VERSION 5.7 ;
  NOWIREEXTENSIONATPIN ON ;
  DIVIDERCHAR "/" ;
  BUSBITCHARS "[]" ;
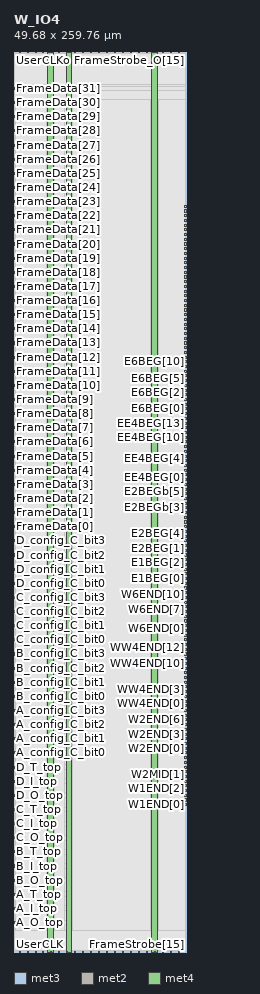
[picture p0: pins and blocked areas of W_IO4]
MACRO W_IO4
  CLASS BLOCK ;
  FOREIGN W_IO4 ;
  ORIGIN 0.000 0.000 ;
  SIZE 49.680 BY 259.760 ;
  PIN A_I_top
    DIRECTION OUTPUT ;
    USE SIGNAL ;
    ANTENNADIFFAREA 0.445500 ;
    PORT
      LAYER met3 ;
        RECT 0.000 12.280 0.600 12.880 ;
    END
  END A_I_top
  PIN A_O_top
    DIRECTION INPUT ;
    USE SIGNAL ;
    ANTENNAGATEAREA 0.159000 ;
    PORT
      LAYER met3 ;
        RECT 0.000 8.200 0.600 8.800 ;
    END
  END A_O_top
  PIN A_T_top
    DIRECTION OUTPUT ;
    USE SIGNAL ;
    ANTENNADIFFAREA 0.445500 ;
    PORT
      LAYER met3 ;
        RECT 0.000 16.360 0.600 16.960 ;
    END
  END A_T_top
  PIN A_config_C_bit0
    DIRECTION OUTPUT ;
    USE SIGNAL ;
    ANTENNADIFFAREA 0.445500 ;
    PORT
      LAYER met3 ;
        RECT 0.000 57.160 0.600 57.760 ;
    END
  END A_config_C_bit0
  PIN A_config_C_bit1
    DIRECTION OUTPUT ;
    USE SIGNAL ;
    ANTENNADIFFAREA 0.445500 ;
    PORT
      LAYER met3 ;
        RECT 0.000 61.240 0.600 61.840 ;
    END
  END A_config_C_bit1
  PIN A_config_C_bit2
    DIRECTION OUTPUT ;
    USE SIGNAL ;
    ANTENNADIFFAREA 0.445500 ;
    PORT
      LAYER met3 ;
        RECT 0.000 65.320 0.600 65.920 ;
    END
  END A_config_C_bit2
  PIN A_config_C_bit3
    DIRECTION OUTPUT ;
    USE SIGNAL ;
    ANTENNADIFFAREA 0.445500 ;
    PORT
      LAYER met3 ;
        RECT 0.000 69.400 0.600 70.000 ;
    END
  END A_config_C_bit3
  PIN B_I_top
    DIRECTION OUTPUT ;
    USE SIGNAL ;
    ANTENNADIFFAREA 0.445500 ;
    PORT
      LAYER met3 ;
        RECT 0.000 24.520 0.600 25.120 ;
    END
  END B_I_top
  PIN B_O_top
    DIRECTION INPUT ;
    USE SIGNAL ;
    ANTENNAGATEAREA 0.159000 ;
    PORT
      LAYER met3 ;
        RECT 0.000 20.440 0.600 21.040 ;
    END
  END B_O_top
  PIN B_T_top
    DIRECTION OUTPUT ;
    USE SIGNAL ;
    ANTENNADIFFAREA 0.445500 ;
    PORT
      LAYER met3 ;
        RECT 0.000 28.600 0.600 29.200 ;
    END
  END B_T_top
  PIN B_config_C_bit0
    DIRECTION OUTPUT ;
    USE SIGNAL ;
    ANTENNADIFFAREA 0.445500 ;
    PORT
      LAYER met3 ;
        RECT 0.000 73.480 0.600 74.080 ;
    END
  END B_config_C_bit0
  PIN B_config_C_bit1
    DIRECTION OUTPUT ;
    USE SIGNAL ;
    ANTENNADIFFAREA 0.445500 ;
    PORT
      LAYER met3 ;
        RECT 0.000 77.560 0.600 78.160 ;
    END
  END B_config_C_bit1
  PIN B_config_C_bit2
    DIRECTION OUTPUT ;
    USE SIGNAL ;
    ANTENNADIFFAREA 0.445500 ;
    PORT
      LAYER met3 ;
        RECT 0.000 81.640 0.600 82.240 ;
    END
  END B_config_C_bit2
  PIN B_config_C_bit3
    DIRECTION OUTPUT ;
    USE SIGNAL ;
    ANTENNADIFFAREA 0.445500 ;
    PORT
      LAYER met3 ;
        RECT 0.000 85.720 0.600 86.320 ;
    END
  END B_config_C_bit3
  PIN C_I_top
    DIRECTION OUTPUT ;
    USE SIGNAL ;
    ANTENNADIFFAREA 0.445500 ;
    PORT
      LAYER met3 ;
        RECT 0.000 36.760 0.600 37.360 ;
    END
  END C_I_top
  PIN C_O_top
    DIRECTION INPUT ;
    USE SIGNAL ;
    ANTENNAGATEAREA 0.159000 ;
    PORT
      LAYER met3 ;
        RECT 0.000 32.680 0.600 33.280 ;
    END
  END C_O_top
  PIN C_T_top
    DIRECTION OUTPUT ;
    USE SIGNAL ;
    ANTENNADIFFAREA 0.445500 ;
    PORT
      LAYER met3 ;
        RECT 0.000 40.840 0.600 41.440 ;
    END
  END C_T_top
  PIN C_config_C_bit0
    DIRECTION OUTPUT ;
    USE SIGNAL ;
    ANTENNADIFFAREA 0.445500 ;
    PORT
      LAYER met3 ;
        RECT 0.000 89.800 0.600 90.400 ;
    END
  END C_config_C_bit0
  PIN C_config_C_bit1
    DIRECTION OUTPUT ;
    USE SIGNAL ;
    ANTENNADIFFAREA 0.445500 ;
    PORT
      LAYER met3 ;
        RECT 0.000 93.880 0.600 94.480 ;
    END
  END C_config_C_bit1
  PIN C_config_C_bit2
    DIRECTION OUTPUT ;
    USE SIGNAL ;
    ANTENNADIFFAREA 0.445500 ;
    PORT
      LAYER met3 ;
        RECT 0.000 97.960 0.600 98.560 ;
    END
  END C_config_C_bit2
  PIN C_config_C_bit3
    DIRECTION OUTPUT ;
    USE SIGNAL ;
    ANTENNADIFFAREA 0.445500 ;
    PORT
      LAYER met3 ;
        RECT 0.000 102.040 0.600 102.640 ;
    END
  END C_config_C_bit3
  PIN D_I_top
    DIRECTION OUTPUT ;
    USE SIGNAL ;
    ANTENNADIFFAREA 0.445500 ;
    PORT
      LAYER met3 ;
        RECT 0.000 49.000 0.600 49.600 ;
    END
  END D_I_top
  PIN D_O_top
    DIRECTION INPUT ;
    USE SIGNAL ;
    ANTENNAGATEAREA 0.213000 ;
    PORT
      LAYER met3 ;
        RECT 0.000 44.920 0.600 45.520 ;
    END
  END D_O_top
  PIN D_T_top
    DIRECTION OUTPUT ;
    USE SIGNAL ;
    ANTENNADIFFAREA 0.445500 ;
    PORT
      LAYER met3 ;
        RECT 0.000 53.080 0.600 53.680 ;
    END
  END D_T_top
  PIN D_config_C_bit0
    DIRECTION OUTPUT ;
    USE SIGNAL ;
    ANTENNADIFFAREA 0.445500 ;
    PORT
      LAYER met3 ;
        RECT 0.000 106.120 0.600 106.720 ;
    END
  END D_config_C_bit0
  PIN D_config_C_bit1
    DIRECTION OUTPUT ;
    USE SIGNAL ;
    ANTENNADIFFAREA 0.445500 ;
    PORT
      LAYER met3 ;
        RECT 0.000 110.200 0.600 110.800 ;
    END
  END D_config_C_bit1
  PIN D_config_C_bit2
    DIRECTION OUTPUT ;
    USE SIGNAL ;
    ANTENNADIFFAREA 0.445500 ;
    PORT
      LAYER met3 ;
        RECT 0.000 114.280 0.600 114.880 ;
    END
  END D_config_C_bit2
  PIN D_config_C_bit3
    DIRECTION OUTPUT ;
    USE SIGNAL ;
    ANTENNADIFFAREA 0.445500 ;
    PORT
      LAYER met3 ;
        RECT 0.000 118.360 0.600 118.960 ;
    END
  END D_config_C_bit3
  PIN E1BEG[0]
    DIRECTION OUTPUT ;
    USE SIGNAL ;
    ANTENNADIFFAREA 0.445500 ;
    PORT
      LAYER met3 ;
        RECT 49.080 107.480 49.680 108.080 ;
    END
  END E1BEG[0]
  PIN E1BEG[1]
    DIRECTION OUTPUT ;
    USE SIGNAL ;
    ANTENNADIFFAREA 0.445500 ;
    PORT
      LAYER met3 ;
        RECT 49.080 108.840 49.680 109.440 ;
    END
  END E1BEG[1]
  PIN E1BEG[2]
    DIRECTION OUTPUT ;
    USE SIGNAL ;
    ANTENNADIFFAREA 0.445500 ;
    PORT
      LAYER met3 ;
        RECT 49.080 110.200 49.680 110.800 ;
    END
  END E1BEG[2]
  PIN E1BEG[3]
    DIRECTION OUTPUT ;
    USE SIGNAL ;
    ANTENNADIFFAREA 0.445500 ;
    PORT
      LAYER met3 ;
        RECT 49.080 111.560 49.680 112.160 ;
    END
  END E1BEG[3]
  PIN E2BEG[0]
    DIRECTION OUTPUT ;
    USE SIGNAL ;
    ANTENNADIFFAREA 0.445500 ;
    PORT
      LAYER met3 ;
        RECT 49.080 112.920 49.680 113.520 ;
    END
  END E2BEG[0]
  PIN E2BEG[1]
    DIRECTION OUTPUT ;
    USE SIGNAL ;
    ANTENNADIFFAREA 0.445500 ;
    PORT
      LAYER met3 ;
        RECT 49.080 114.280 49.680 114.880 ;
    END
  END E2BEG[1]
  PIN E2BEG[2]
    DIRECTION OUTPUT ;
    USE SIGNAL ;
    ANTENNADIFFAREA 0.445500 ;
    PORT
      LAYER met3 ;
        RECT 49.080 115.640 49.680 116.240 ;
    END
  END E2BEG[2]
  PIN E2BEG[3]
    DIRECTION OUTPUT ;
    USE SIGNAL ;
    ANTENNADIFFAREA 0.445500 ;
    PORT
      LAYER met3 ;
        RECT 49.080 117.000 49.680 117.600 ;
    END
  END E2BEG[3]
  PIN E2BEG[4]
    DIRECTION OUTPUT ;
    USE SIGNAL ;
    ANTENNADIFFAREA 0.445500 ;
    PORT
      LAYER met3 ;
        RECT 49.080 118.360 49.680 118.960 ;
    END
  END E2BEG[4]
  PIN E2BEG[5]
    DIRECTION OUTPUT ;
    USE SIGNAL ;
    ANTENNADIFFAREA 0.445500 ;
    PORT
      LAYER met3 ;
        RECT 49.080 119.720 49.680 120.320 ;
    END
  END E2BEG[5]
  PIN E2BEG[6]
    DIRECTION OUTPUT ;
    USE SIGNAL ;
    ANTENNADIFFAREA 0.445500 ;
    PORT
      LAYER met3 ;
        RECT 49.080 121.080 49.680 121.680 ;
    END
  END E2BEG[6]
  PIN E2BEG[7]
    DIRECTION OUTPUT ;
    USE SIGNAL ;
    ANTENNADIFFAREA 0.445500 ;
    PORT
      LAYER met3 ;
        RECT 49.080 122.440 49.680 123.040 ;
    END
  END E2BEG[7]
  PIN E2BEGb[0]
    DIRECTION OUTPUT ;
    USE SIGNAL ;
    ANTENNADIFFAREA 0.445500 ;
    PORT
      LAYER met3 ;
        RECT 49.080 123.800 49.680 124.400 ;
    END
  END E2BEGb[0]
  PIN E2BEGb[1]
    DIRECTION OUTPUT ;
    USE SIGNAL ;
    ANTENNADIFFAREA 0.445500 ;
    PORT
      LAYER met3 ;
        RECT 49.080 125.160 49.680 125.760 ;
    END
  END E2BEGb[1]
  PIN E2BEGb[2]
    DIRECTION OUTPUT ;
    USE SIGNAL ;
    ANTENNADIFFAREA 0.445500 ;
    PORT
      LAYER met3 ;
        RECT 49.080 126.520 49.680 127.120 ;
    END
  END E2BEGb[2]
  PIN E2BEGb[3]
    DIRECTION OUTPUT ;
    USE SIGNAL ;
    ANTENNADIFFAREA 0.445500 ;
    PORT
      LAYER met3 ;
        RECT 49.080 127.880 49.680 128.480 ;
    END
  END E2BEGb[3]
  PIN E2BEGb[4]
    DIRECTION OUTPUT ;
    USE SIGNAL ;
    ANTENNADIFFAREA 0.445500 ;
    PORT
      LAYER met3 ;
        RECT 49.080 129.240 49.680 129.840 ;
    END
  END E2BEGb[4]
  PIN E2BEGb[5]
    DIRECTION OUTPUT ;
    USE SIGNAL ;
    ANTENNADIFFAREA 0.445500 ;
    PORT
      LAYER met3 ;
        RECT 49.080 130.600 49.680 131.200 ;
    END
  END E2BEGb[5]
  PIN E2BEGb[6]
    DIRECTION OUTPUT ;
    USE SIGNAL ;
    ANTENNADIFFAREA 0.445500 ;
    PORT
      LAYER met3 ;
        RECT 49.080 131.960 49.680 132.560 ;
    END
  END E2BEGb[6]
  PIN E2BEGb[7]
    DIRECTION OUTPUT ;
    USE SIGNAL ;
    ANTENNADIFFAREA 0.445500 ;
    PORT
      LAYER met3 ;
        RECT 49.080 133.320 49.680 133.920 ;
    END
  END E2BEGb[7]
  PIN E6BEG[0]
    DIRECTION OUTPUT ;
    USE SIGNAL ;
    ANTENNADIFFAREA 0.445500 ;
    PORT
      LAYER met3 ;
        RECT 49.080 156.440 49.680 157.040 ;
    END
  END E6BEG[0]
  PIN E6BEG[10]
    DIRECTION OUTPUT ;
    USE SIGNAL ;
    ANTENNADIFFAREA 0.445500 ;
    PORT
      LAYER met3 ;
        RECT 49.080 170.040 49.680 170.640 ;
    END
  END E6BEG[10]
  PIN E6BEG[11]
    DIRECTION OUTPUT ;
    USE SIGNAL ;
    ANTENNADIFFAREA 0.445500 ;
    PORT
      LAYER met3 ;
        RECT 49.080 171.400 49.680 172.000 ;
    END
  END E6BEG[11]
  PIN E6BEG[1]
    DIRECTION OUTPUT ;
    USE SIGNAL ;
    ANTENNADIFFAREA 0.445500 ;
    PORT
      LAYER met3 ;
        RECT 49.080 157.800 49.680 158.400 ;
    END
  END E6BEG[1]
  PIN E6BEG[2]
    DIRECTION OUTPUT ;
    USE SIGNAL ;
    ANTENNADIFFAREA 0.445500 ;
    PORT
      LAYER met3 ;
        RECT 49.080 159.160 49.680 159.760 ;
    END
  END E6BEG[2]
  PIN E6BEG[3]
    DIRECTION OUTPUT ;
    USE SIGNAL ;
    ANTENNADIFFAREA 0.445500 ;
    PORT
      LAYER met3 ;
        RECT 49.080 160.520 49.680 161.120 ;
    END
  END E6BEG[3]
  PIN E6BEG[4]
    DIRECTION OUTPUT ;
    USE SIGNAL ;
    ANTENNADIFFAREA 0.445500 ;
    PORT
      LAYER met3 ;
        RECT 49.080 161.880 49.680 162.480 ;
    END
  END E6BEG[4]
  PIN E6BEG[5]
    DIRECTION OUTPUT ;
    USE SIGNAL ;
    ANTENNADIFFAREA 0.445500 ;
    PORT
      LAYER met3 ;
        RECT 49.080 163.240 49.680 163.840 ;
    END
  END E6BEG[5]
  PIN E6BEG[6]
    DIRECTION OUTPUT ;
    USE SIGNAL ;
    ANTENNADIFFAREA 0.445500 ;
    PORT
      LAYER met3 ;
        RECT 49.080 164.600 49.680 165.200 ;
    END
  END E6BEG[6]
  PIN E6BEG[7]
    DIRECTION OUTPUT ;
    USE SIGNAL ;
    ANTENNADIFFAREA 0.445500 ;
    PORT
      LAYER met3 ;
        RECT 49.080 165.960 49.680 166.560 ;
    END
  END E6BEG[7]
  PIN E6BEG[8]
    DIRECTION OUTPUT ;
    USE SIGNAL ;
    ANTENNADIFFAREA 0.445500 ;
    PORT
      LAYER met3 ;
        RECT 49.080 167.320 49.680 167.920 ;
    END
  END E6BEG[8]
  PIN E6BEG[9]
    DIRECTION OUTPUT ;
    USE SIGNAL ;
    ANTENNADIFFAREA 0.445500 ;
    PORT
      LAYER met3 ;
        RECT 49.080 168.680 49.680 169.280 ;
    END
  END E6BEG[9]
  PIN EE4BEG[0]
    DIRECTION OUTPUT ;
    USE SIGNAL ;
    ANTENNADIFFAREA 0.445500 ;
    PORT
      LAYER met3 ;
        RECT 49.080 134.680 49.680 135.280 ;
    END
  END EE4BEG[0]
  PIN EE4BEG[10]
    DIRECTION OUTPUT ;
    USE SIGNAL ;
    ANTENNADIFFAREA 0.445500 ;
    PORT
      LAYER met3 ;
        RECT 49.080 148.280 49.680 148.880 ;
    END
  END EE4BEG[10]
  PIN EE4BEG[11]
    DIRECTION OUTPUT ;
    USE SIGNAL ;
    ANTENNADIFFAREA 0.445500 ;
    PORT
      LAYER met3 ;
        RECT 49.080 149.640 49.680 150.240 ;
    END
  END EE4BEG[11]
  PIN EE4BEG[12]
    DIRECTION OUTPUT ;
    USE SIGNAL ;
    ANTENNADIFFAREA 0.445500 ;
    PORT
      LAYER met3 ;
        RECT 49.080 151.000 49.680 151.600 ;
    END
  END EE4BEG[12]
  PIN EE4BEG[13]
    DIRECTION OUTPUT ;
    USE SIGNAL ;
    ANTENNADIFFAREA 0.445500 ;
    PORT
      LAYER met3 ;
        RECT 49.080 152.360 49.680 152.960 ;
    END
  END EE4BEG[13]
  PIN EE4BEG[14]
    DIRECTION OUTPUT ;
    USE SIGNAL ;
    ANTENNADIFFAREA 0.445500 ;
    PORT
      LAYER met3 ;
        RECT 49.080 153.720 49.680 154.320 ;
    END
  END EE4BEG[14]
  PIN EE4BEG[15]
    DIRECTION OUTPUT ;
    USE SIGNAL ;
    ANTENNADIFFAREA 0.445500 ;
    PORT
      LAYER met3 ;
        RECT 49.080 155.080 49.680 155.680 ;
    END
  END EE4BEG[15]
  PIN EE4BEG[1]
    DIRECTION OUTPUT ;
    USE SIGNAL ;
    ANTENNADIFFAREA 0.445500 ;
    PORT
      LAYER met3 ;
        RECT 49.080 136.040 49.680 136.640 ;
    END
  END EE4BEG[1]
  PIN EE4BEG[2]
    DIRECTION OUTPUT ;
    USE SIGNAL ;
    ANTENNADIFFAREA 0.445500 ;
    PORT
      LAYER met3 ;
        RECT 49.080 137.400 49.680 138.000 ;
    END
  END EE4BEG[2]
  PIN EE4BEG[3]
    DIRECTION OUTPUT ;
    USE SIGNAL ;
    ANTENNADIFFAREA 0.445500 ;
    PORT
      LAYER met3 ;
        RECT 49.080 138.760 49.680 139.360 ;
    END
  END EE4BEG[3]
  PIN EE4BEG[4]
    DIRECTION OUTPUT ;
    USE SIGNAL ;
    ANTENNADIFFAREA 0.445500 ;
    PORT
      LAYER met3 ;
        RECT 49.080 140.120 49.680 140.720 ;
    END
  END EE4BEG[4]
  PIN EE4BEG[5]
    DIRECTION OUTPUT ;
    USE SIGNAL ;
    ANTENNADIFFAREA 0.445500 ;
    PORT
      LAYER met3 ;
        RECT 49.080 141.480 49.680 142.080 ;
    END
  END EE4BEG[5]
  PIN EE4BEG[6]
    DIRECTION OUTPUT ;
    USE SIGNAL ;
    ANTENNADIFFAREA 0.445500 ;
    PORT
      LAYER met3 ;
        RECT 49.080 142.840 49.680 143.440 ;
    END
  END EE4BEG[6]
  PIN EE4BEG[7]
    DIRECTION OUTPUT ;
    USE SIGNAL ;
    ANTENNADIFFAREA 0.445500 ;
    PORT
      LAYER met3 ;
        RECT 49.080 144.200 49.680 144.800 ;
    END
  END EE4BEG[7]
  PIN EE4BEG[8]
    DIRECTION OUTPUT ;
    USE SIGNAL ;
    ANTENNADIFFAREA 0.445500 ;
    PORT
      LAYER met3 ;
        RECT 49.080 145.560 49.680 146.160 ;
    END
  END EE4BEG[8]
  PIN EE4BEG[9]
    DIRECTION OUTPUT ;
    USE SIGNAL ;
    ANTENNADIFFAREA 0.445500 ;
    PORT
      LAYER met3 ;
        RECT 49.080 146.920 49.680 147.520 ;
    END
  END EE4BEG[9]
  PIN FrameData[0]
    DIRECTION INPUT ;
    USE SIGNAL ;
    ANTENNAGATEAREA 0.196500 ;
    PORT
      LAYER met3 ;
        RECT 0.000 122.440 0.600 123.040 ;
    END
  END FrameData[0]
  PIN FrameData[10]
    DIRECTION INPUT ;
    USE SIGNAL ;
    ANTENNAGATEAREA 0.213000 ;
    PORT
      LAYER met3 ;
        RECT 0.000 163.240 0.600 163.840 ;
    END
  END FrameData[10]
  PIN FrameData[11]
    DIRECTION INPUT ;
    USE SIGNAL ;
    ANTENNAGATEAREA 0.213000 ;
    PORT
      LAYER met3 ;
        RECT 0.000 167.320 0.600 167.920 ;
    END
  END FrameData[11]
  PIN FrameData[12]
    DIRECTION INPUT ;
    USE SIGNAL ;
    ANTENNAGATEAREA 0.213000 ;
    PORT
      LAYER met3 ;
        RECT 0.000 171.400 0.600 172.000 ;
    END
  END FrameData[12]
  PIN FrameData[13]
    DIRECTION INPUT ;
    USE SIGNAL ;
    ANTENNAGATEAREA 0.213000 ;
    PORT
      LAYER met3 ;
        RECT 0.000 175.480 0.600 176.080 ;
    END
  END FrameData[13]
  PIN FrameData[14]
    DIRECTION INPUT ;
    USE SIGNAL ;
    ANTENNAGATEAREA 0.213000 ;
    PORT
      LAYER met3 ;
        RECT 0.000 179.560 0.600 180.160 ;
    END
  END FrameData[14]
  PIN FrameData[15]
    DIRECTION INPUT ;
    USE SIGNAL ;
    ANTENNAGATEAREA 0.213000 ;
    PORT
      LAYER met3 ;
        RECT 0.000 183.640 0.600 184.240 ;
    END
  END FrameData[15]
  PIN FrameData[16]
    DIRECTION INPUT ;
    USE SIGNAL ;
    ANTENNAGATEAREA 0.196500 ;
    PORT
      LAYER met3 ;
        RECT 0.000 187.720 0.600 188.320 ;
    END
  END FrameData[16]
  PIN FrameData[17]
    DIRECTION INPUT ;
    USE SIGNAL ;
    ANTENNAGATEAREA 0.196500 ;
    PORT
      LAYER met3 ;
        RECT 0.000 191.800 0.600 192.400 ;
    END
  END FrameData[17]
  PIN FrameData[18]
    DIRECTION INPUT ;
    USE SIGNAL ;
    ANTENNAGATEAREA 0.213000 ;
    PORT
      LAYER met3 ;
        RECT 0.000 195.880 0.600 196.480 ;
    END
  END FrameData[18]
  PIN FrameData[19]
    DIRECTION INPUT ;
    USE SIGNAL ;
    ANTENNAGATEAREA 0.213000 ;
    PORT
      LAYER met3 ;
        RECT 0.000 199.960 0.600 200.560 ;
    END
  END FrameData[19]
  PIN FrameData[1]
    DIRECTION INPUT ;
    USE SIGNAL ;
    ANTENNAGATEAREA 0.196500 ;
    PORT
      LAYER met3 ;
        RECT 0.000 126.520 0.600 127.120 ;
    END
  END FrameData[1]
  PIN FrameData[20]
    DIRECTION INPUT ;
    USE SIGNAL ;
    ANTENNAGATEAREA 0.159000 ;
    PORT
      LAYER met3 ;
        RECT 0.000 204.040 0.600 204.640 ;
    END
  END FrameData[20]
  PIN FrameData[21]
    DIRECTION INPUT ;
    USE SIGNAL ;
    ANTENNAGATEAREA 0.159000 ;
    PORT
      LAYER met3 ;
        RECT 0.000 208.120 0.600 208.720 ;
    END
  END FrameData[21]
  PIN FrameData[22]
    DIRECTION INPUT ;
    USE SIGNAL ;
    ANTENNAGATEAREA 0.159000 ;
    PORT
      LAYER met3 ;
        RECT 0.000 212.200 0.600 212.800 ;
    END
  END FrameData[22]
  PIN FrameData[23]
    DIRECTION INPUT ;
    USE SIGNAL ;
    ANTENNAGATEAREA 0.159000 ;
    PORT
      LAYER met3 ;
        RECT 0.000 216.280 0.600 216.880 ;
    END
  END FrameData[23]
  PIN FrameData[24]
    DIRECTION INPUT ;
    USE SIGNAL ;
    ANTENNAGATEAREA 0.159000 ;
    PORT
      LAYER met3 ;
        RECT 0.000 220.360 0.600 220.960 ;
    END
  END FrameData[24]
  PIN FrameData[25]
    DIRECTION INPUT ;
    USE SIGNAL ;
    ANTENNAGATEAREA 0.213000 ;
    PORT
      LAYER met3 ;
        RECT 0.000 224.440 0.600 225.040 ;
    END
  END FrameData[25]
  PIN FrameData[26]
    DIRECTION INPUT ;
    USE SIGNAL ;
    ANTENNAGATEAREA 0.159000 ;
    PORT
      LAYER met3 ;
        RECT 0.000 228.520 0.600 229.120 ;
    END
  END FrameData[26]
  PIN FrameData[27]
    DIRECTION INPUT ;
    USE SIGNAL ;
    ANTENNAGATEAREA 0.159000 ;
    PORT
      LAYER met3 ;
        RECT 0.000 232.600 0.600 233.200 ;
    END
  END FrameData[27]
  PIN FrameData[28]
    DIRECTION INPUT ;
    USE SIGNAL ;
    ANTENNAGATEAREA 0.159000 ;
    PORT
      LAYER met3 ;
        RECT 0.000 236.680 0.600 237.280 ;
    END
  END FrameData[28]
  PIN FrameData[29]
    DIRECTION INPUT ;
    USE SIGNAL ;
    ANTENNAGATEAREA 0.213000 ;
    PORT
      LAYER met3 ;
        RECT 0.000 240.760 0.600 241.360 ;
    END
  END FrameData[29]
  PIN FrameData[2]
    DIRECTION INPUT ;
    USE SIGNAL ;
    ANTENNAGATEAREA 0.126000 ;
    PORT
      LAYER met3 ;
        RECT 0.000 130.600 0.600 131.200 ;
    END
  END FrameData[2]
  PIN FrameData[30]
    DIRECTION INPUT ;
    USE SIGNAL ;
    ANTENNAGATEAREA 0.159000 ;
    PORT
      LAYER met3 ;
        RECT 0.000 244.840 0.600 245.440 ;
    END
  END FrameData[30]
  PIN FrameData[31]
    DIRECTION INPUT ;
    USE SIGNAL ;
    ANTENNAGATEAREA 0.159000 ;
    PORT
      LAYER met3 ;
        RECT 0.000 248.920 0.600 249.520 ;
    END
  END FrameData[31]
  PIN FrameData[3]
    DIRECTION INPUT ;
    USE SIGNAL ;
    ANTENNAGATEAREA 0.213000 ;
    PORT
      LAYER met3 ;
        RECT 0.000 134.680 0.600 135.280 ;
    END
  END FrameData[3]
  PIN FrameData[4]
    DIRECTION INPUT ;
    USE SIGNAL ;
    ANTENNAGATEAREA 0.213000 ;
    PORT
      LAYER met3 ;
        RECT 0.000 138.760 0.600 139.360 ;
    END
  END FrameData[4]
  PIN FrameData[5]
    DIRECTION INPUT ;
    USE SIGNAL ;
    ANTENNAGATEAREA 0.213000 ;
    PORT
      LAYER met3 ;
        RECT 0.000 142.840 0.600 143.440 ;
    END
  END FrameData[5]
  PIN FrameData[6]
    DIRECTION INPUT ;
    USE SIGNAL ;
    ANTENNAGATEAREA 0.213000 ;
    PORT
      LAYER met3 ;
        RECT 0.000 146.920 0.600 147.520 ;
    END
  END FrameData[6]
  PIN FrameData[7]
    DIRECTION INPUT ;
    USE SIGNAL ;
    ANTENNAGATEAREA 0.213000 ;
    PORT
      LAYER met3 ;
        RECT 0.000 151.000 0.600 151.600 ;
    END
  END FrameData[7]
  PIN FrameData[8]
    DIRECTION INPUT ;
    USE SIGNAL ;
    ANTENNAGATEAREA 0.213000 ;
    PORT
      LAYER met3 ;
        RECT 0.000 155.080 0.600 155.680 ;
    END
  END FrameData[8]
  PIN FrameData[9]
    DIRECTION INPUT ;
    USE SIGNAL ;
    ANTENNAGATEAREA 0.213000 ;
    PORT
      LAYER met3 ;
        RECT 0.000 159.160 0.600 159.760 ;
    END
  END FrameData[9]
  PIN FrameData_O[0]
    DIRECTION OUTPUT ;
    USE SIGNAL ;
    ANTENNADIFFAREA 0.445500 ;
    PORT
      LAYER met3 ;
        RECT 49.080 172.760 49.680 173.360 ;
    END
  END FrameData_O[0]
  PIN FrameData_O[10]
    DIRECTION OUTPUT ;
    USE SIGNAL ;
    ANTENNADIFFAREA 0.445500 ;
    PORT
      LAYER met3 ;
        RECT 49.080 186.360 49.680 186.960 ;
    END
  END FrameData_O[10]
  PIN FrameData_O[11]
    DIRECTION OUTPUT ;
    USE SIGNAL ;
    ANTENNADIFFAREA 0.445500 ;
    PORT
      LAYER met3 ;
        RECT 49.080 187.720 49.680 188.320 ;
    END
  END FrameData_O[11]
  PIN FrameData_O[12]
    DIRECTION OUTPUT ;
    USE SIGNAL ;
    ANTENNADIFFAREA 0.445500 ;
    PORT
      LAYER met3 ;
        RECT 49.080 189.080 49.680 189.680 ;
    END
  END FrameData_O[12]
  PIN FrameData_O[13]
    DIRECTION OUTPUT ;
    USE SIGNAL ;
    ANTENNADIFFAREA 0.445500 ;
    PORT
      LAYER met3 ;
        RECT 49.080 190.440 49.680 191.040 ;
    END
  END FrameData_O[13]
  PIN FrameData_O[14]
    DIRECTION OUTPUT ;
    USE SIGNAL ;
    ANTENNADIFFAREA 0.445500 ;
    PORT
      LAYER met3 ;
        RECT 49.080 191.800 49.680 192.400 ;
    END
  END FrameData_O[14]
  PIN FrameData_O[15]
    DIRECTION OUTPUT ;
    USE SIGNAL ;
    ANTENNADIFFAREA 0.445500 ;
    PORT
      LAYER met3 ;
        RECT 49.080 193.160 49.680 193.760 ;
    END
  END FrameData_O[15]
  PIN FrameData_O[16]
    DIRECTION OUTPUT ;
    USE SIGNAL ;
    ANTENNADIFFAREA 0.445500 ;
    PORT
      LAYER met3 ;
        RECT 49.080 194.520 49.680 195.120 ;
    END
  END FrameData_O[16]
  PIN FrameData_O[17]
    DIRECTION OUTPUT ;
    USE SIGNAL ;
    ANTENNADIFFAREA 0.445500 ;
    PORT
      LAYER met3 ;
        RECT 49.080 195.880 49.680 196.480 ;
    END
  END FrameData_O[17]
  PIN FrameData_O[18]
    DIRECTION OUTPUT ;
    USE SIGNAL ;
    ANTENNADIFFAREA 0.445500 ;
    PORT
      LAYER met3 ;
        RECT 49.080 197.240 49.680 197.840 ;
    END
  END FrameData_O[18]
  PIN FrameData_O[19]
    DIRECTION OUTPUT ;
    USE SIGNAL ;
    ANTENNADIFFAREA 0.445500 ;
    PORT
      LAYER met3 ;
        RECT 49.080 198.600 49.680 199.200 ;
    END
  END FrameData_O[19]
  PIN FrameData_O[1]
    DIRECTION OUTPUT ;
    USE SIGNAL ;
    ANTENNADIFFAREA 0.445500 ;
    PORT
      LAYER met3 ;
        RECT 49.080 174.120 49.680 174.720 ;
    END
  END FrameData_O[1]
  PIN FrameData_O[20]
    DIRECTION OUTPUT ;
    USE SIGNAL ;
    ANTENNADIFFAREA 0.445500 ;
    PORT
      LAYER met3 ;
        RECT 49.080 199.960 49.680 200.560 ;
    END
  END FrameData_O[20]
  PIN FrameData_O[21]
    DIRECTION OUTPUT ;
    USE SIGNAL ;
    ANTENNADIFFAREA 0.445500 ;
    PORT
      LAYER met3 ;
        RECT 49.080 201.320 49.680 201.920 ;
    END
  END FrameData_O[21]
  PIN FrameData_O[22]
    DIRECTION OUTPUT ;
    USE SIGNAL ;
    ANTENNADIFFAREA 0.445500 ;
    PORT
      LAYER met3 ;
        RECT 49.080 202.680 49.680 203.280 ;
    END
  END FrameData_O[22]
  PIN FrameData_O[23]
    DIRECTION OUTPUT ;
    USE SIGNAL ;
    ANTENNADIFFAREA 0.445500 ;
    PORT
      LAYER met3 ;
        RECT 49.080 204.040 49.680 204.640 ;
    END
  END FrameData_O[23]
  PIN FrameData_O[24]
    DIRECTION OUTPUT ;
    USE SIGNAL ;
    ANTENNADIFFAREA 0.445500 ;
    PORT
      LAYER met3 ;
        RECT 49.080 205.400 49.680 206.000 ;
    END
  END FrameData_O[24]
  PIN FrameData_O[25]
    DIRECTION OUTPUT ;
    USE SIGNAL ;
    ANTENNADIFFAREA 0.445500 ;
    PORT
      LAYER met3 ;
        RECT 49.080 206.760 49.680 207.360 ;
    END
  END FrameData_O[25]
  PIN FrameData_O[26]
    DIRECTION OUTPUT ;
    USE SIGNAL ;
    ANTENNADIFFAREA 0.445500 ;
    PORT
      LAYER met3 ;
        RECT 49.080 208.120 49.680 208.720 ;
    END
  END FrameData_O[26]
  PIN FrameData_O[27]
    DIRECTION OUTPUT ;
    USE SIGNAL ;
    ANTENNADIFFAREA 0.445500 ;
    PORT
      LAYER met3 ;
        RECT 49.080 209.480 49.680 210.080 ;
    END
  END FrameData_O[27]
  PIN FrameData_O[28]
    DIRECTION OUTPUT ;
    USE SIGNAL ;
    ANTENNADIFFAREA 0.445500 ;
    PORT
      LAYER met3 ;
        RECT 49.080 210.840 49.680 211.440 ;
    END
  END FrameData_O[28]
  PIN FrameData_O[29]
    DIRECTION OUTPUT ;
    USE SIGNAL ;
    ANTENNADIFFAREA 0.445500 ;
    PORT
      LAYER met3 ;
        RECT 49.080 212.200 49.680 212.800 ;
    END
  END FrameData_O[29]
  PIN FrameData_O[2]
    DIRECTION OUTPUT ;
    USE SIGNAL ;
    ANTENNADIFFAREA 0.445500 ;
    PORT
      LAYER met3 ;
        RECT 49.080 175.480 49.680 176.080 ;
    END
  END FrameData_O[2]
  PIN FrameData_O[30]
    DIRECTION OUTPUT ;
    USE SIGNAL ;
    ANTENNADIFFAREA 0.445500 ;
    PORT
      LAYER met3 ;
        RECT 49.080 213.560 49.680 214.160 ;
    END
  END FrameData_O[30]
  PIN FrameData_O[31]
    DIRECTION OUTPUT ;
    USE SIGNAL ;
    ANTENNADIFFAREA 0.445500 ;
    PORT
      LAYER met3 ;
        RECT 49.080 214.920 49.680 215.520 ;
    END
  END FrameData_O[31]
  PIN FrameData_O[3]
    DIRECTION OUTPUT ;
    USE SIGNAL ;
    ANTENNADIFFAREA 0.445500 ;
    PORT
      LAYER met3 ;
        RECT 49.080 176.840 49.680 177.440 ;
    END
  END FrameData_O[3]
  PIN FrameData_O[4]
    DIRECTION OUTPUT ;
    USE SIGNAL ;
    ANTENNADIFFAREA 0.445500 ;
    PORT
      LAYER met3 ;
        RECT 49.080 178.200 49.680 178.800 ;
    END
  END FrameData_O[4]
  PIN FrameData_O[5]
    DIRECTION OUTPUT ;
    USE SIGNAL ;
    ANTENNADIFFAREA 0.445500 ;
    PORT
      LAYER met3 ;
        RECT 49.080 179.560 49.680 180.160 ;
    END
  END FrameData_O[5]
  PIN FrameData_O[6]
    DIRECTION OUTPUT ;
    USE SIGNAL ;
    ANTENNADIFFAREA 0.445500 ;
    PORT
      LAYER met3 ;
        RECT 49.080 180.920 49.680 181.520 ;
    END
  END FrameData_O[6]
  PIN FrameData_O[7]
    DIRECTION OUTPUT ;
    USE SIGNAL ;
    ANTENNADIFFAREA 0.445500 ;
    PORT
      LAYER met3 ;
        RECT 49.080 182.280 49.680 182.880 ;
    END
  END FrameData_O[7]
  PIN FrameData_O[8]
    DIRECTION OUTPUT ;
    USE SIGNAL ;
    ANTENNADIFFAREA 0.445500 ;
    PORT
      LAYER met3 ;
        RECT 49.080 183.640 49.680 184.240 ;
    END
  END FrameData_O[8]
  PIN FrameData_O[9]
    DIRECTION OUTPUT ;
    USE SIGNAL ;
    ANTENNADIFFAREA 0.445500 ;
    PORT
      LAYER met3 ;
        RECT 49.080 185.000 49.680 185.600 ;
    END
  END FrameData_O[9]
  PIN FrameStrobe[0]
    DIRECTION INPUT ;
    USE SIGNAL ;
    ANTENNAGATEAREA 0.213000 ;
    PORT
      LAYER met2 ;
        RECT 3.770 0.000 4.050 0.280 ;
    END
  END FrameStrobe[0]
  PIN FrameStrobe[10]
    DIRECTION INPUT ;
    USE SIGNAL ;
    ANTENNAGATEAREA 0.631200 ;
    ANTENNADIFFAREA 0.434700 ;
    PORT
      LAYER met2 ;
        RECT 26.770 0.000 27.050 0.280 ;
    END
  END FrameStrobe[10]
  PIN FrameStrobe[11]
    DIRECTION INPUT ;
    USE SIGNAL ;
    ANTENNAGATEAREA 0.631200 ;
    ANTENNADIFFAREA 0.434700 ;
    PORT
      LAYER met2 ;
        RECT 29.070 0.000 29.350 0.280 ;
    END
  END FrameStrobe[11]
  PIN FrameStrobe[12]
    DIRECTION INPUT ;
    USE SIGNAL ;
    ANTENNAGATEAREA 0.631200 ;
    ANTENNADIFFAREA 0.434700 ;
    PORT
      LAYER met2 ;
        RECT 31.370 0.000 31.650 0.280 ;
    END
  END FrameStrobe[12]
  PIN FrameStrobe[13]
    DIRECTION INPUT ;
    USE SIGNAL ;
    ANTENNAGATEAREA 0.631200 ;
    ANTENNADIFFAREA 0.434700 ;
    PORT
      LAYER met2 ;
        RECT 33.670 0.000 33.950 0.280 ;
    END
  END FrameStrobe[13]
  PIN FrameStrobe[14]
    DIRECTION INPUT ;
    USE SIGNAL ;
    ANTENNAGATEAREA 0.631200 ;
    ANTENNADIFFAREA 0.434700 ;
    PORT
      LAYER met2 ;
        RECT 35.970 0.000 36.250 0.280 ;
    END
  END FrameStrobe[14]
  PIN FrameStrobe[15]
    DIRECTION INPUT ;
    USE SIGNAL ;
    ANTENNAGATEAREA 0.631200 ;
    ANTENNADIFFAREA 0.434700 ;
    PORT
      LAYER met2 ;
        RECT 38.270 0.000 38.550 0.280 ;
    END
  END FrameStrobe[15]
  PIN FrameStrobe[16]
    DIRECTION INPUT ;
    USE SIGNAL ;
    ANTENNAGATEAREA 0.631200 ;
    ANTENNADIFFAREA 0.434700 ;
    PORT
      LAYER met2 ;
        RECT 40.570 0.000 40.850 0.280 ;
    END
  END FrameStrobe[16]
  PIN FrameStrobe[17]
    DIRECTION INPUT ;
    USE SIGNAL ;
    ANTENNAGATEAREA 0.631200 ;
    ANTENNADIFFAREA 0.434700 ;
    PORT
      LAYER met2 ;
        RECT 42.870 0.000 43.150 0.280 ;
    END
  END FrameStrobe[17]
  PIN FrameStrobe[18]
    DIRECTION INPUT ;
    USE SIGNAL ;
    ANTENNAGATEAREA 0.631200 ;
    ANTENNADIFFAREA 0.434700 ;
    PORT
      LAYER met2 ;
        RECT 45.170 0.000 45.450 0.280 ;
    END
  END FrameStrobe[18]
  PIN FrameStrobe[19]
    DIRECTION INPUT ;
    USE SIGNAL ;
    ANTENNAGATEAREA 0.631200 ;
    ANTENNADIFFAREA 0.434700 ;
    PORT
      LAYER met2 ;
        RECT 47.470 0.000 47.750 0.280 ;
    END
  END FrameStrobe[19]
  PIN FrameStrobe[1]
    DIRECTION INPUT ;
    USE SIGNAL ;
    ANTENNAGATEAREA 0.560700 ;
    ANTENNADIFFAREA 0.434700 ;
    PORT
      LAYER met2 ;
        RECT 6.070 0.000 6.350 0.280 ;
    END
  END FrameStrobe[1]
  PIN FrameStrobe[2]
    DIRECTION INPUT ;
    USE SIGNAL ;
    ANTENNAGATEAREA 0.444000 ;
    PORT
      LAYER met2 ;
        RECT 8.370 0.000 8.650 0.280 ;
    END
  END FrameStrobe[2]
  PIN FrameStrobe[3]
    DIRECTION INPUT ;
    USE SIGNAL ;
    ANTENNAGATEAREA 0.647700 ;
    ANTENNADIFFAREA 0.434700 ;
    PORT
      LAYER met2 ;
        RECT 10.670 0.000 10.950 0.280 ;
    END
  END FrameStrobe[3]
  PIN FrameStrobe[4]
    DIRECTION INPUT ;
    USE SIGNAL ;
    ANTENNAGATEAREA 0.196500 ;
    PORT
      LAYER met2 ;
        RECT 12.970 0.000 13.250 0.280 ;
    END
  END FrameStrobe[4]
  PIN FrameStrobe[5]
    DIRECTION INPUT ;
    USE SIGNAL ;
    ANTENNAGATEAREA 0.631200 ;
    ANTENNADIFFAREA 0.434700 ;
    PORT
      LAYER met2 ;
        RECT 15.270 0.000 15.550 0.280 ;
    END
  END FrameStrobe[5]
  PIN FrameStrobe[6]
    DIRECTION INPUT ;
    USE SIGNAL ;
    ANTENNAGATEAREA 0.631200 ;
    ANTENNADIFFAREA 0.434700 ;
    PORT
      LAYER met2 ;
        RECT 17.570 0.000 17.850 0.280 ;
    END
  END FrameStrobe[6]
  PIN FrameStrobe[7]
    DIRECTION INPUT ;
    USE SIGNAL ;
    ANTENNAGATEAREA 1.065900 ;
    ANTENNADIFFAREA 0.869400 ;
    PORT
      LAYER met2 ;
        RECT 19.870 0.000 20.150 0.280 ;
    END
  END FrameStrobe[7]
  PIN FrameStrobe[8]
    DIRECTION INPUT ;
    USE SIGNAL ;
    ANTENNAGATEAREA 0.631200 ;
    ANTENNADIFFAREA 0.434700 ;
    PORT
      LAYER met2 ;
        RECT 22.170 0.000 22.450 0.280 ;
    END
  END FrameStrobe[8]
  PIN FrameStrobe[9]
    DIRECTION INPUT ;
    USE SIGNAL ;
    ANTENNAGATEAREA 0.631200 ;
    ANTENNADIFFAREA 0.434700 ;
    PORT
      LAYER met2 ;
        RECT 24.470 0.000 24.750 0.280 ;
    END
  END FrameStrobe[9]
  PIN FrameStrobe_O[0]
    DIRECTION OUTPUT ;
    USE SIGNAL ;
    ANTENNADIFFAREA 0.445500 ;
    PORT
      LAYER met2 ;
        RECT 3.770 259.480 4.050 259.760 ;
    END
  END FrameStrobe_O[0]
  PIN FrameStrobe_O[10]
    DIRECTION OUTPUT ;
    USE SIGNAL ;
    ANTENNADIFFAREA 0.445500 ;
    PORT
      LAYER met2 ;
        RECT 26.770 259.480 27.050 259.760 ;
    END
  END FrameStrobe_O[10]
  PIN FrameStrobe_O[11]
    DIRECTION OUTPUT ;
    USE SIGNAL ;
    ANTENNADIFFAREA 0.445500 ;
    PORT
      LAYER met2 ;
        RECT 29.070 259.480 29.350 259.760 ;
    END
  END FrameStrobe_O[11]
  PIN FrameStrobe_O[12]
    DIRECTION OUTPUT ;
    USE SIGNAL ;
    ANTENNADIFFAREA 0.445500 ;
    PORT
      LAYER met2 ;
        RECT 31.370 259.480 31.650 259.760 ;
    END
  END FrameStrobe_O[12]
  PIN FrameStrobe_O[13]
    DIRECTION OUTPUT ;
    USE SIGNAL ;
    ANTENNADIFFAREA 0.445500 ;
    PORT
      LAYER met2 ;
        RECT 33.670 259.480 33.950 259.760 ;
    END
  END FrameStrobe_O[13]
  PIN FrameStrobe_O[14]
    DIRECTION OUTPUT ;
    USE SIGNAL ;
    ANTENNADIFFAREA 0.445500 ;
    PORT
      LAYER met2 ;
        RECT 35.970 259.480 36.250 259.760 ;
    END
  END FrameStrobe_O[14]
  PIN FrameStrobe_O[15]
    DIRECTION OUTPUT ;
    USE SIGNAL ;
    ANTENNADIFFAREA 0.445500 ;
    PORT
      LAYER met2 ;
        RECT 38.270 259.480 38.550 259.760 ;
    END
  END FrameStrobe_O[15]
  PIN FrameStrobe_O[16]
    DIRECTION OUTPUT ;
    USE SIGNAL ;
    ANTENNADIFFAREA 0.445500 ;
    PORT
      LAYER met2 ;
        RECT 40.570 259.480 40.850 259.760 ;
    END
  END FrameStrobe_O[16]
  PIN FrameStrobe_O[17]
    DIRECTION OUTPUT ;
    USE SIGNAL ;
    ANTENNADIFFAREA 0.445500 ;
    PORT
      LAYER met2 ;
        RECT 42.870 259.480 43.150 259.760 ;
    END
  END FrameStrobe_O[17]
  PIN FrameStrobe_O[18]
    DIRECTION OUTPUT ;
    USE SIGNAL ;
    ANTENNADIFFAREA 0.445500 ;
    PORT
      LAYER met2 ;
        RECT 45.170 259.480 45.450 259.760 ;
    END
  END FrameStrobe_O[18]
  PIN FrameStrobe_O[19]
    DIRECTION OUTPUT ;
    USE SIGNAL ;
    ANTENNADIFFAREA 0.445500 ;
    PORT
      LAYER met2 ;
        RECT 47.470 259.480 47.750 259.760 ;
    END
  END FrameStrobe_O[19]
  PIN FrameStrobe_O[1]
    DIRECTION OUTPUT ;
    USE SIGNAL ;
    ANTENNADIFFAREA 0.445500 ;
    PORT
      LAYER met2 ;
        RECT 6.070 259.480 6.350 259.760 ;
    END
  END FrameStrobe_O[1]
  PIN FrameStrobe_O[2]
    DIRECTION OUTPUT ;
    USE SIGNAL ;
    ANTENNADIFFAREA 0.445500 ;
    PORT
      LAYER met2 ;
        RECT 8.370 259.480 8.650 259.760 ;
    END
  END FrameStrobe_O[2]
  PIN FrameStrobe_O[3]
    DIRECTION OUTPUT ;
    USE SIGNAL ;
    ANTENNADIFFAREA 0.445500 ;
    PORT
      LAYER met2 ;
        RECT 10.670 259.480 10.950 259.760 ;
    END
  END FrameStrobe_O[3]
  PIN FrameStrobe_O[4]
    DIRECTION OUTPUT ;
    USE SIGNAL ;
    ANTENNADIFFAREA 0.445500 ;
    PORT
      LAYER met2 ;
        RECT 12.970 259.480 13.250 259.760 ;
    END
  END FrameStrobe_O[4]
  PIN FrameStrobe_O[5]
    DIRECTION OUTPUT ;
    USE SIGNAL ;
    ANTENNADIFFAREA 0.445500 ;
    PORT
      LAYER met2 ;
        RECT 15.270 259.480 15.550 259.760 ;
    END
  END FrameStrobe_O[5]
  PIN FrameStrobe_O[6]
    DIRECTION OUTPUT ;
    USE SIGNAL ;
    ANTENNADIFFAREA 0.445500 ;
    PORT
      LAYER met2 ;
        RECT 17.570 259.480 17.850 259.760 ;
    END
  END FrameStrobe_O[6]
  PIN FrameStrobe_O[7]
    DIRECTION OUTPUT ;
    USE SIGNAL ;
    ANTENNADIFFAREA 0.445500 ;
    PORT
      LAYER met2 ;
        RECT 19.870 259.480 20.150 259.760 ;
    END
  END FrameStrobe_O[7]
  PIN FrameStrobe_O[8]
    DIRECTION OUTPUT ;
    USE SIGNAL ;
    ANTENNADIFFAREA 0.445500 ;
    PORT
      LAYER met2 ;
        RECT 22.170 259.480 22.450 259.760 ;
    END
  END FrameStrobe_O[8]
  PIN FrameStrobe_O[9]
    DIRECTION OUTPUT ;
    USE SIGNAL ;
    ANTENNADIFFAREA 0.445500 ;
    PORT
      LAYER met2 ;
        RECT 24.470 259.480 24.750 259.760 ;
    END
  END FrameStrobe_O[9]
  PIN UserCLK
    DIRECTION INPUT ;
    USE SIGNAL ;
    ANTENNAGATEAREA 1.704000 ;
    PORT
      LAYER met2 ;
        RECT 1.470 0.000 1.750 0.280 ;
    END
  END UserCLK
  PIN UserCLKo
    DIRECTION OUTPUT ;
    USE SIGNAL ;
    ANTENNADIFFAREA 0.340600 ;
    PORT
      LAYER met2 ;
        RECT 1.470 259.480 1.750 259.760 ;
    END
  END UserCLKo
  PIN VGND
    DIRECTION INOUT ;
    USE GROUND ;
    PORT
      LAYER met4 ;
        RECT 15.020 0.000 16.620 259.760 ;
    END
  END VGND
  PIN VPWR
    DIRECTION INOUT ;
    USE POWER ;
    PORT
      LAYER met4 ;
        RECT 9.720 0.000 11.320 259.760 ;
    END
    PORT
      LAYER met4 ;
        RECT 39.720 0.000 41.320 259.760 ;
    END
  END VPWR
  PIN W1END[0]
    DIRECTION INPUT ;
    USE SIGNAL ;
    ANTENNAGATEAREA 0.213000 ;
    PORT
      LAYER met3 ;
        RECT 49.080 42.200 49.680 42.800 ;
    END
  END W1END[0]
  PIN W1END[1]
    DIRECTION INPUT ;
    USE SIGNAL ;
    ANTENNAGATEAREA 0.213000 ;
    PORT
      LAYER met3 ;
        RECT 49.080 43.560 49.680 44.160 ;
    END
  END W1END[1]
  PIN W1END[2]
    DIRECTION INPUT ;
    USE SIGNAL ;
    ANTENNAGATEAREA 0.213000 ;
    PORT
      LAYER met3 ;
        RECT 49.080 44.920 49.680 45.520 ;
    END
  END W1END[2]
  PIN W1END[3]
    DIRECTION INPUT ;
    USE SIGNAL ;
    ANTENNAGATEAREA 0.213000 ;
    PORT
      LAYER met3 ;
        RECT 49.080 46.280 49.680 46.880 ;
    END
  END W1END[3]
  PIN W2END[0]
    DIRECTION INPUT ;
    USE SIGNAL ;
    ANTENNAGATEAREA 0.159000 ;
    PORT
      LAYER met3 ;
        RECT 49.080 58.520 49.680 59.120 ;
    END
  END W2END[0]
  PIN W2END[1]
    DIRECTION INPUT ;
    USE SIGNAL ;
    ANTENNAGATEAREA 0.213000 ;
    PORT
      LAYER met3 ;
        RECT 49.080 59.880 49.680 60.480 ;
    END
  END W2END[1]
  PIN W2END[2]
    DIRECTION INPUT ;
    USE SIGNAL ;
    ANTENNAGATEAREA 0.213000 ;
    PORT
      LAYER met3 ;
        RECT 49.080 61.240 49.680 61.840 ;
    END
  END W2END[2]
  PIN W2END[3]
    DIRECTION INPUT ;
    USE SIGNAL ;
    ANTENNAGATEAREA 0.159000 ;
    PORT
      LAYER met3 ;
        RECT 49.080 62.600 49.680 63.200 ;
    END
  END W2END[3]
  PIN W2END[4]
    DIRECTION INPUT ;
    USE SIGNAL ;
    ANTENNAGATEAREA 0.159000 ;
    PORT
      LAYER met3 ;
        RECT 49.080 63.960 49.680 64.560 ;
    END
  END W2END[4]
  PIN W2END[5]
    DIRECTION INPUT ;
    USE SIGNAL ;
    ANTENNAGATEAREA 0.159000 ;
    PORT
      LAYER met3 ;
        RECT 49.080 65.320 49.680 65.920 ;
    END
  END W2END[5]
  PIN W2END[6]
    DIRECTION INPUT ;
    USE SIGNAL ;
    ANTENNAGATEAREA 0.159000 ;
    PORT
      LAYER met3 ;
        RECT 49.080 66.680 49.680 67.280 ;
    END
  END W2END[6]
  PIN W2END[7]
    DIRECTION INPUT ;
    USE SIGNAL ;
    ANTENNAGATEAREA 0.126000 ;
    PORT
      LAYER met3 ;
        RECT 49.080 68.040 49.680 68.640 ;
    END
  END W2END[7]
  PIN W2MID[0]
    DIRECTION INPUT ;
    USE SIGNAL ;
    ANTENNAGATEAREA 0.196500 ;
    PORT
      LAYER met3 ;
        RECT 49.080 47.640 49.680 48.240 ;
    END
  END W2MID[0]
  PIN W2MID[1]
    DIRECTION INPUT ;
    USE SIGNAL ;
    ANTENNAGATEAREA 0.196500 ;
    PORT
      LAYER met3 ;
        RECT 49.080 49.000 49.680 49.600 ;
    END
  END W2MID[1]
  PIN W2MID[2]
    DIRECTION INPUT ;
    USE SIGNAL ;
    ANTENNAGATEAREA 0.213000 ;
    PORT
      LAYER met3 ;
        RECT 49.080 50.360 49.680 50.960 ;
    END
  END W2MID[2]
  PIN W2MID[3]
    DIRECTION INPUT ;
    USE SIGNAL ;
    ANTENNAGATEAREA 0.213000 ;
    PORT
      LAYER met3 ;
        RECT 49.080 51.720 49.680 52.320 ;
    END
  END W2MID[3]
  PIN W2MID[4]
    DIRECTION INPUT ;
    USE SIGNAL ;
    ANTENNAGATEAREA 0.213000 ;
    PORT
      LAYER met3 ;
        RECT 49.080 53.080 49.680 53.680 ;
    END
  END W2MID[4]
  PIN W2MID[5]
    DIRECTION INPUT ;
    USE SIGNAL ;
    ANTENNAGATEAREA 0.213000 ;
    PORT
      LAYER met3 ;
        RECT 49.080 54.440 49.680 55.040 ;
    END
  END W2MID[5]
  PIN W2MID[6]
    DIRECTION INPUT ;
    USE SIGNAL ;
    ANTENNAGATEAREA 0.159000 ;
    PORT
      LAYER met3 ;
        RECT 49.080 55.800 49.680 56.400 ;
    END
  END W2MID[6]
  PIN W2MID[7]
    DIRECTION INPUT ;
    USE SIGNAL ;
    ANTENNAGATEAREA 0.196500 ;
    PORT
      LAYER met3 ;
        RECT 49.080 57.160 49.680 57.760 ;
    END
  END W2MID[7]
  PIN W6END[0]
    DIRECTION INPUT ;
    USE SIGNAL ;
    ANTENNAGATEAREA 0.196500 ;
    PORT
      LAYER met3 ;
        RECT 49.080 91.160 49.680 91.760 ;
    END
  END W6END[0]
  PIN W6END[10]
    DIRECTION INPUT ;
    USE SIGNAL ;
    ANTENNAGATEAREA 0.126000 ;
    PORT
      LAYER met3 ;
        RECT 49.080 104.760 49.680 105.360 ;
    END
  END W6END[10]
  PIN W6END[11]
    DIRECTION INPUT ;
    USE SIGNAL ;
    ANTENNAGATEAREA 0.196500 ;
    PORT
      LAYER met3 ;
        RECT 49.080 106.120 49.680 106.720 ;
    END
  END W6END[11]
  PIN W6END[1]
    DIRECTION INPUT ;
    USE SIGNAL ;
    ANTENNAGATEAREA 0.213000 ;
    PORT
      LAYER met3 ;
        RECT 49.080 92.520 49.680 93.120 ;
    END
  END W6END[1]
  PIN W6END[2]
    DIRECTION INPUT ;
    USE SIGNAL ;
    ANTENNAGATEAREA 0.196500 ;
    PORT
      LAYER met3 ;
        RECT 49.080 93.880 49.680 94.480 ;
    END
  END W6END[2]
  PIN W6END[3]
    DIRECTION INPUT ;
    USE SIGNAL ;
    ANTENNAGATEAREA 0.213000 ;
    PORT
      LAYER met3 ;
        RECT 49.080 95.240 49.680 95.840 ;
    END
  END W6END[3]
  PIN W6END[4]
    DIRECTION INPUT ;
    USE SIGNAL ;
    ANTENNAGATEAREA 0.196500 ;
    PORT
      LAYER met3 ;
        RECT 49.080 96.600 49.680 97.200 ;
    END
  END W6END[4]
  PIN W6END[5]
    DIRECTION INPUT ;
    USE SIGNAL ;
    ANTENNAGATEAREA 0.213000 ;
    PORT
      LAYER met3 ;
        RECT 49.080 97.960 49.680 98.560 ;
    END
  END W6END[5]
  PIN W6END[6]
    DIRECTION INPUT ;
    USE SIGNAL ;
    ANTENNAGATEAREA 0.213000 ;
    PORT
      LAYER met3 ;
        RECT 49.080 99.320 49.680 99.920 ;
    END
  END W6END[6]
  PIN W6END[7]
    DIRECTION INPUT ;
    USE SIGNAL ;
    ANTENNAGATEAREA 0.213000 ;
    PORT
      LAYER met3 ;
        RECT 49.080 100.680 49.680 101.280 ;
    END
  END W6END[7]
  PIN W6END[8]
    DIRECTION INPUT ;
    USE SIGNAL ;
    ANTENNAGATEAREA 0.126000 ;
    PORT
      LAYER met3 ;
        RECT 49.080 102.040 49.680 102.640 ;
    END
  END W6END[8]
  PIN W6END[9]
    DIRECTION INPUT ;
    USE SIGNAL ;
    ANTENNAGATEAREA 0.196500 ;
    PORT
      LAYER met3 ;
        RECT 49.080 103.400 49.680 104.000 ;
    END
  END W6END[9]
  PIN WW4END[0]
    DIRECTION INPUT ;
    USE SIGNAL ;
    ANTENNAGATEAREA 0.196500 ;
    PORT
      LAYER met3 ;
        RECT 49.080 69.400 49.680 70.000 ;
    END
  END WW4END[0]
  PIN WW4END[10]
    DIRECTION INPUT ;
    USE SIGNAL ;
    ANTENNAGATEAREA 0.196500 ;
    PORT
      LAYER met3 ;
        RECT 49.080 83.000 49.680 83.600 ;
    END
  END WW4END[10]
  PIN WW4END[11]
    DIRECTION INPUT ;
    USE SIGNAL ;
    ANTENNAGATEAREA 0.126000 ;
    PORT
      LAYER met3 ;
        RECT 49.080 84.360 49.680 84.960 ;
    END
  END WW4END[11]
  PIN WW4END[12]
    DIRECTION INPUT ;
    USE SIGNAL ;
    ANTENNAGATEAREA 0.196500 ;
    PORT
      LAYER met3 ;
        RECT 49.080 85.720 49.680 86.320 ;
    END
  END WW4END[12]
  PIN WW4END[13]
    DIRECTION INPUT ;
    USE SIGNAL ;
    ANTENNAGATEAREA 0.126000 ;
    PORT
      LAYER met3 ;
        RECT 49.080 87.080 49.680 87.680 ;
    END
  END WW4END[13]
  PIN WW4END[14]
    DIRECTION INPUT ;
    USE SIGNAL ;
    ANTENNAGATEAREA 0.126000 ;
    PORT
      LAYER met3 ;
        RECT 49.080 88.440 49.680 89.040 ;
    END
  END WW4END[14]
  PIN WW4END[15]
    DIRECTION INPUT ;
    USE SIGNAL ;
    ANTENNAGATEAREA 0.196500 ;
    PORT
      LAYER met3 ;
        RECT 49.080 89.800 49.680 90.400 ;
    END
  END WW4END[15]
  PIN WW4END[1]
    DIRECTION INPUT ;
    USE SIGNAL ;
    ANTENNAGATEAREA 0.196500 ;
    PORT
      LAYER met3 ;
        RECT 49.080 70.760 49.680 71.360 ;
    END
  END WW4END[1]
  PIN WW4END[2]
    DIRECTION INPUT ;
    USE SIGNAL ;
    ANTENNAGATEAREA 0.196500 ;
    PORT
      LAYER met3 ;
        RECT 49.080 72.120 49.680 72.720 ;
    END
  END WW4END[2]
  PIN WW4END[3]
    DIRECTION INPUT ;
    USE SIGNAL ;
    ANTENNAGATEAREA 0.126000 ;
    PORT
      LAYER met3 ;
        RECT 49.080 73.480 49.680 74.080 ;
    END
  END WW4END[3]
  PIN WW4END[4]
    DIRECTION INPUT ;
    USE SIGNAL ;
    ANTENNAGATEAREA 0.196500 ;
    PORT
      LAYER met3 ;
        RECT 49.080 74.840 49.680 75.440 ;
    END
  END WW4END[4]
  PIN WW4END[5]
    DIRECTION INPUT ;
    USE SIGNAL ;
    ANTENNAGATEAREA 0.126000 ;
    PORT
      LAYER met3 ;
        RECT 49.080 76.200 49.680 76.800 ;
    END
  END WW4END[5]
  PIN WW4END[6]
    DIRECTION INPUT ;
    USE SIGNAL ;
    ANTENNAGATEAREA 0.213000 ;
    PORT
      LAYER met3 ;
        RECT 49.080 77.560 49.680 78.160 ;
    END
  END WW4END[6]
  PIN WW4END[7]
    DIRECTION INPUT ;
    USE SIGNAL ;
    ANTENNAGATEAREA 0.196500 ;
    PORT
      LAYER met3 ;
        RECT 49.080 78.920 49.680 79.520 ;
    END
  END WW4END[7]
  PIN WW4END[8]
    DIRECTION INPUT ;
    USE SIGNAL ;
    ANTENNAGATEAREA 0.196500 ;
    PORT
      LAYER met3 ;
        RECT 49.080 80.280 49.680 80.880 ;
    END
  END WW4END[8]
  PIN WW4END[9]
    DIRECTION INPUT ;
    USE SIGNAL ;
    ANTENNAGATEAREA 0.196500 ;
    PORT
      LAYER met3 ;
        RECT 49.080 81.640 49.680 82.240 ;
    END
  END WW4END[9]
  OBS
      LAYER nwell ;
        RECT 5.330 8.075 44.350 250.430 ;
      LAYER li1 ;
        RECT 5.520 8.075 44.160 250.325 ;
      LAYER met1 ;
        RECT 0.070 2.080 49.610 250.480 ;
      LAYER met2 ;
        RECT 0.090 259.200 1.190 259.690 ;
        RECT 2.030 259.200 3.490 259.690 ;
        RECT 4.330 259.200 5.790 259.690 ;
        RECT 6.630 259.200 8.090 259.690 ;
        RECT 8.930 259.200 10.390 259.690 ;
        RECT 11.230 259.200 12.690 259.690 ;
        RECT 13.530 259.200 14.990 259.690 ;
        RECT 15.830 259.200 17.290 259.690 ;
        RECT 18.130 259.200 19.590 259.690 ;
        RECT 20.430 259.200 21.890 259.690 ;
        RECT 22.730 259.200 24.190 259.690 ;
        RECT 25.030 259.200 26.490 259.690 ;
        RECT 27.330 259.200 28.790 259.690 ;
        RECT 29.630 259.200 31.090 259.690 ;
        RECT 31.930 259.200 33.390 259.690 ;
        RECT 34.230 259.200 35.690 259.690 ;
        RECT 36.530 259.200 37.990 259.690 ;
        RECT 38.830 259.200 40.290 259.690 ;
        RECT 41.130 259.200 42.590 259.690 ;
        RECT 43.430 259.200 44.890 259.690 ;
        RECT 45.730 259.200 47.190 259.690 ;
        RECT 48.030 259.200 49.580 259.690 ;
        RECT 0.090 0.560 49.580 259.200 ;
        RECT 0.090 0.070 1.190 0.560 ;
        RECT 2.030 0.070 3.490 0.560 ;
        RECT 4.330 0.070 5.790 0.560 ;
        RECT 6.630 0.070 8.090 0.560 ;
        RECT 8.930 0.070 10.390 0.560 ;
        RECT 11.230 0.070 12.690 0.560 ;
        RECT 13.530 0.070 14.990 0.560 ;
        RECT 15.830 0.070 17.290 0.560 ;
        RECT 18.130 0.070 19.590 0.560 ;
        RECT 20.430 0.070 21.890 0.560 ;
        RECT 22.730 0.070 24.190 0.560 ;
        RECT 25.030 0.070 26.490 0.560 ;
        RECT 27.330 0.070 28.790 0.560 ;
        RECT 29.630 0.070 31.090 0.560 ;
        RECT 31.930 0.070 33.390 0.560 ;
        RECT 34.230 0.070 35.690 0.560 ;
        RECT 36.530 0.070 37.990 0.560 ;
        RECT 38.830 0.070 40.290 0.560 ;
        RECT 41.130 0.070 42.590 0.560 ;
        RECT 43.430 0.070 44.890 0.560 ;
        RECT 45.730 0.070 47.190 0.560 ;
        RECT 48.030 0.070 49.580 0.560 ;
      LAYER met3 ;
        RECT 0.065 249.920 49.410 250.405 ;
        RECT 1.000 248.520 49.410 249.920 ;
        RECT 0.065 245.840 49.410 248.520 ;
        RECT 1.000 244.440 49.410 245.840 ;
        RECT 0.065 241.760 49.410 244.440 ;
        RECT 1.000 240.360 49.410 241.760 ;
        RECT 0.065 237.680 49.410 240.360 ;
        RECT 1.000 236.280 49.410 237.680 ;
        RECT 0.065 233.600 49.410 236.280 ;
        RECT 1.000 232.200 49.410 233.600 ;
        RECT 0.065 229.520 49.410 232.200 ;
        RECT 1.000 228.120 49.410 229.520 ;
        RECT 0.065 225.440 49.410 228.120 ;
        RECT 1.000 224.040 49.410 225.440 ;
        RECT 0.065 221.360 49.410 224.040 ;
        RECT 1.000 219.960 49.410 221.360 ;
        RECT 0.065 217.280 49.410 219.960 ;
        RECT 1.000 215.920 49.410 217.280 ;
        RECT 1.000 215.880 48.680 215.920 ;
        RECT 0.065 213.200 48.680 215.880 ;
        RECT 1.000 211.800 48.680 213.200 ;
        RECT 0.065 209.120 48.680 211.800 ;
        RECT 1.000 207.720 48.680 209.120 ;
        RECT 0.065 205.040 48.680 207.720 ;
        RECT 1.000 203.640 48.680 205.040 ;
        RECT 0.065 200.960 48.680 203.640 ;
        RECT 1.000 199.560 48.680 200.960 ;
        RECT 0.065 196.880 48.680 199.560 ;
        RECT 1.000 195.480 48.680 196.880 ;
        RECT 0.065 192.800 48.680 195.480 ;
        RECT 1.000 191.400 48.680 192.800 ;
        RECT 0.065 188.720 48.680 191.400 ;
        RECT 1.000 187.320 48.680 188.720 ;
        RECT 0.065 184.640 48.680 187.320 ;
        RECT 1.000 183.240 48.680 184.640 ;
        RECT 0.065 180.560 48.680 183.240 ;
        RECT 1.000 179.160 48.680 180.560 ;
        RECT 0.065 176.480 48.680 179.160 ;
        RECT 1.000 175.080 48.680 176.480 ;
        RECT 0.065 172.400 48.680 175.080 ;
        RECT 1.000 171.000 48.680 172.400 ;
        RECT 0.065 168.320 48.680 171.000 ;
        RECT 1.000 166.920 48.680 168.320 ;
        RECT 0.065 164.240 48.680 166.920 ;
        RECT 1.000 162.840 48.680 164.240 ;
        RECT 0.065 160.160 48.680 162.840 ;
        RECT 1.000 158.760 48.680 160.160 ;
        RECT 0.065 156.080 48.680 158.760 ;
        RECT 1.000 154.680 48.680 156.080 ;
        RECT 0.065 152.000 48.680 154.680 ;
        RECT 1.000 150.600 48.680 152.000 ;
        RECT 0.065 147.920 48.680 150.600 ;
        RECT 1.000 146.520 48.680 147.920 ;
        RECT 0.065 143.840 48.680 146.520 ;
        RECT 1.000 142.440 48.680 143.840 ;
        RECT 0.065 139.760 48.680 142.440 ;
        RECT 1.000 138.360 48.680 139.760 ;
        RECT 0.065 135.680 48.680 138.360 ;
        RECT 1.000 134.280 48.680 135.680 ;
        RECT 0.065 131.600 48.680 134.280 ;
        RECT 1.000 130.200 48.680 131.600 ;
        RECT 0.065 127.520 48.680 130.200 ;
        RECT 1.000 126.120 48.680 127.520 ;
        RECT 0.065 123.440 48.680 126.120 ;
        RECT 1.000 122.040 48.680 123.440 ;
        RECT 0.065 119.360 48.680 122.040 ;
        RECT 1.000 117.960 48.680 119.360 ;
        RECT 0.065 115.280 48.680 117.960 ;
        RECT 1.000 113.880 48.680 115.280 ;
        RECT 0.065 111.200 48.680 113.880 ;
        RECT 1.000 109.800 48.680 111.200 ;
        RECT 0.065 107.120 48.680 109.800 ;
        RECT 1.000 105.720 48.680 107.120 ;
        RECT 0.065 103.040 48.680 105.720 ;
        RECT 1.000 101.640 48.680 103.040 ;
        RECT 0.065 98.960 48.680 101.640 ;
        RECT 1.000 97.560 48.680 98.960 ;
        RECT 0.065 94.880 48.680 97.560 ;
        RECT 1.000 93.480 48.680 94.880 ;
        RECT 0.065 90.800 48.680 93.480 ;
        RECT 1.000 89.400 48.680 90.800 ;
        RECT 0.065 86.720 48.680 89.400 ;
        RECT 1.000 85.320 48.680 86.720 ;
        RECT 0.065 82.640 48.680 85.320 ;
        RECT 1.000 81.240 48.680 82.640 ;
        RECT 0.065 78.560 48.680 81.240 ;
        RECT 1.000 77.160 48.680 78.560 ;
        RECT 0.065 74.480 48.680 77.160 ;
        RECT 1.000 73.080 48.680 74.480 ;
        RECT 0.065 70.400 48.680 73.080 ;
        RECT 1.000 69.000 48.680 70.400 ;
        RECT 0.065 66.320 48.680 69.000 ;
        RECT 1.000 64.920 48.680 66.320 ;
        RECT 0.065 62.240 48.680 64.920 ;
        RECT 1.000 60.840 48.680 62.240 ;
        RECT 0.065 58.160 48.680 60.840 ;
        RECT 1.000 56.760 48.680 58.160 ;
        RECT 0.065 54.080 48.680 56.760 ;
        RECT 1.000 52.680 48.680 54.080 ;
        RECT 0.065 50.000 48.680 52.680 ;
        RECT 1.000 48.600 48.680 50.000 ;
        RECT 0.065 45.920 48.680 48.600 ;
        RECT 1.000 44.520 48.680 45.920 ;
        RECT 0.065 41.840 48.680 44.520 ;
        RECT 1.000 41.800 48.680 41.840 ;
        RECT 1.000 40.440 49.410 41.800 ;
        RECT 0.065 37.760 49.410 40.440 ;
        RECT 1.000 36.360 49.410 37.760 ;
        RECT 0.065 33.680 49.410 36.360 ;
        RECT 1.000 32.280 49.410 33.680 ;
        RECT 0.065 29.600 49.410 32.280 ;
        RECT 1.000 28.200 49.410 29.600 ;
        RECT 0.065 25.520 49.410 28.200 ;
        RECT 1.000 24.120 49.410 25.520 ;
        RECT 0.065 21.440 49.410 24.120 ;
        RECT 1.000 20.040 49.410 21.440 ;
        RECT 0.065 17.360 49.410 20.040 ;
        RECT 1.000 15.960 49.410 17.360 ;
        RECT 0.065 13.280 49.410 15.960 ;
        RECT 1.000 11.880 49.410 13.280 ;
        RECT 0.065 9.200 49.410 11.880 ;
        RECT 1.000 7.800 49.410 9.200 ;
        RECT 0.065 6.295 49.410 7.800 ;
      LAYER met4 ;
        RECT 0.295 6.295 9.320 245.985 ;
        RECT 11.720 6.295 14.620 245.985 ;
        RECT 17.020 6.295 39.320 245.985 ;
        RECT 41.720 6.295 49.385 245.985 ;
  END
END W_IO4
END LIBRARY

